VERSION 5.7 ;

BUSBITCHARS "[]" ;
DIVIDERCHAR "/" ;

UNITS
  DATABASE MICRONS 1000 ;
END UNITS

MANUFACTURINGGRID 1.0 ;

PROPERTYDEFINITIONS
  LAYER LEF58_TYPE STRING ;
END PROPERTYDEFINITIONS

SITE CoreSite
  CLASS CORE ;
  SYMMETRY Y ;
  SIZE 30 BY 30 ;
END CoreSite

SITE IO_TOP
  CLASS PAD ;
  SIZE 40 BY 40 ;
END IO_TOP

SITE IO_SIDE
  CLASS PAD ;
  SIZE 40 BY 40 ;
END IO_SIDE

SITE IO_CORNER
  CLASS PAD ;
  SIZE 320 BY 320 ;
END IO_CORNER

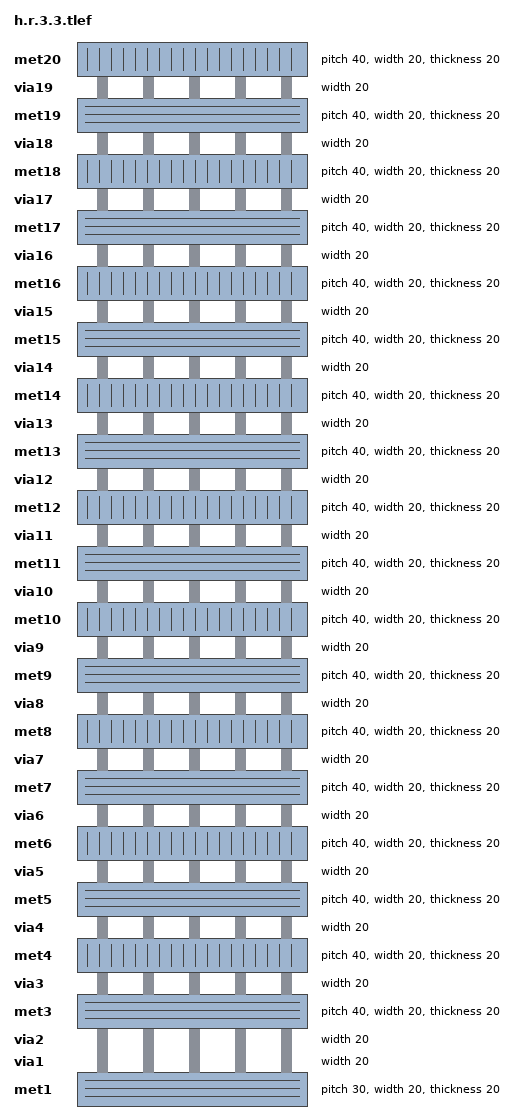
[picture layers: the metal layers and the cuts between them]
LAYER met1
  TYPE ROUTING ;
  DIRECTION HORIZONTAL ;
  MAXWIDTH 20.0 ;
  MINWIDTH 20.0 ;
  WIDTH 20.0 ;
# The pitch for a given routing layer defines the distance between routing tracks in the preferred direction for that layer.
  PITCH 30.0 ;
# Specifies the distance from the top of the ground plane to the bottom of the interconnect.
# HEIGHT  ;
# Specifies the thickness of the interconnect.
  THICKNESS 20.0 ;

END met1

LAYER via1
  TYPE CUT ;
  WIDTH 20.0 ;
END via1

Layer met2
  TYPE ROUTING ;
  DIRECTION VERTICAL ;
  MAXWIDTH 20.0 ;
  MINWIDTH 20.0 ;
  PITCH 40.0 ;
  THICKNESS 20.0 ;
  WIDTH 20.0 ;
END met2

LAYER via2
  TYPE CUT ;
  WIDTH 20.0 ;
END via2

LAYER met3
  TYPE ROUTING ;
  DIRECTION HORIZONTAL ;
  MAXWIDTH 20.0 ;
  MINWIDTH 20.0 ;
  PITCH 40.0 ;
  THICKNESS 20.0 ;
  WIDTH 20.0 ;
END met3

LAYER via3
  TYPE CUT ;
  WIDTH 20.0 ;
END via3

LAYER met4
  TYPE ROUTING ;
  DIRECTION VERTICAL ;
  MAXWIDTH 20.0 ;
  MINWIDTH 20.0 ;
  PITCH 40.0 ;
  THICKNESS 20.0 ;
  WIDTH 20.0 ;
END met4

LAYER via4
  TYPE CUT ;
  WIDTH 20.0 ;
END via4

LAYER met5
  TYPE ROUTING ;
  DIRECTION HORIZONTAL ;
  MAXWIDTH 20.0 ;
  MINWIDTH 20.0 ;
  PITCH 40.0 ;
  THICKNESS 20.0 ;
  WIDTH 20.0 ;
END met5

LAYER via5
  TYPE CUT ;
  WIDTH 20.0 ;
END via5

LAYER met6
  TYPE ROUTING ;
  DIRECTION VERTICAL ;
  MAXWIDTH 20.0 ;
  MINWIDTH 20.0 ;
  PITCH 40.0 ;
  THICKNESS 20.0 ;
  WIDTH 20.0 ;
END met6

LAYER via6
  TYPE CUT ;
  WIDTH 20.0 ;
END via6

LAYER met7
  TYPE ROUTING ;
  DIRECTION HORIZONTAL ;
  MAXWIDTH 20.0 ;
  MINWIDTH 20.0 ;
  PITCH 40.0 ;
  THICKNESS 20.0 ;
  WIDTH 20.0 ;
END met7

LAYER via7
  TYPE CUT ;
  WIDTH 20.0 ;
END via7

LAYER met8
  TYPE ROUTING ;
  DIRECTION VERTICAL ;
  MAXWIDTH 20.0 ;
  MINWIDTH 20.0 ;
  PITCH 40.0 ;
  THICKNESS 20.0 ;
  WIDTH 20.0 ;
END met8

LAYER via8
  TYPE CUT ;
  WIDTH 20.0 ;
END via8

LAYER met9
  TYPE ROUTING ;
  DIRECTION HORIZONTAL ;
  MAXWIDTH 20.0 ;
  MINWIDTH 20.0 ;
  PITCH 40.0 ;
  THICKNESS 20.0 ;
  WIDTH 20.0 ;
END met9

LAYER via9
  TYPE CUT ;
  WIDTH 20.0 ;
END via9

LAYER met10
  TYPE ROUTING ;
  DIRECTION VERTICAL ;
  MAXWIDTH 20.0 ;
  MINWIDTH 20.0 ;
  PITCH 40.0 ;
  THICKNESS 20.0 ;
  WIDTH 20.0 ;
END met10

LAYER via10
  TYPE CUT ;
  WIDTH 20.0 ;
END via10

LAYER met11
  TYPE ROUTING ;
  DIRECTION HORIZONTAL ;
  MAXWIDTH 20.0 ;
  MINWIDTH 20.0 ;
  PITCH 40.0 ;
  THICKNESS 20.0 ;
  WIDTH 20.0 ;
END met11

LAYER via11
  TYPE CUT ;
  WIDTH 20.0 ;
END via11

LAYER met12
  TYPE ROUTING ;
  DIRECTION VERTICAL ;
  MAXWIDTH 20.0 ;
  MINWIDTH 20.0 ;
  PITCH 40.0 ;
  THICKNESS 20.0 ;
  WIDTH 20.0 ;
END met12

LAYER via12
  TYPE CUT ;
  WIDTH 20.0 ;
END via12

LAYER met13
  TYPE ROUTING ;
  DIRECTION HORIZONTAL ;
  MAXWIDTH 20.0 ;
  MINWIDTH 20.0 ;
  PITCH 40.0 ;
  THICKNESS 20.0 ;
  WIDTH 20.0 ;
END met13

LAYER via13
  TYPE CUT ;
  WIDTH 20.0 ;
END via13

LAYER met14
  TYPE ROUTING ;
  DIRECTION VERTICAL ;
  MAXWIDTH 20.0 ;
  MINWIDTH 20.0 ;
  PITCH 40.0 ;
  THICKNESS 20.0 ;
  WIDTH 20.0 ;
END met14

LAYER via14
  TYPE CUT ;
  WIDTH 20.0 ;
END via14

LAYER met15
  TYPE ROUTING ;
  DIRECTION HORIZONTAL ;
  MAXWIDTH 20.0 ;
  MINWIDTH 20.0 ;
  PITCH 40.0 ;
  THICKNESS 20.0 ;
  WIDTH 20.0 ;
END met15

LAYER via15
  TYPE CUT ;
  WIDTH 20.0 ;
END via15

LAYER met16
  TYPE ROUTING ;
  DIRECTION VERTICAL ;
  MAXWIDTH 20.0 ;
  MINWIDTH 20.0 ;
  PITCH 40.0 ;
  THICKNESS 20.0 ;
  WIDTH 20.0 ;
END met16

LAYER via16
  TYPE CUT ;
  WIDTH 20.0 ;
END via16

LAYER met17
  TYPE ROUTING ;
  DIRECTION HORIZONTAL ;
  MAXWIDTH 20.0 ;
  MINWIDTH 20.0 ;
  PITCH 40.0 ;
  THICKNESS 20.0 ;
  WIDTH 20.0 ;
END met17

LAYER via17
  TYPE CUT ;
  WIDTH 20.0 ;
END via17

LAYER met18
  TYPE ROUTING ;
  DIRECTION VERTICAL ;
  MAXWIDTH 20.0 ;
  MINWIDTH 20.0 ;
  PITCH 40.0 ;
  THICKNESS 20.0 ;
  WIDTH 20.0 ;
END met18

LAYER via18
  TYPE CUT ;
  WIDTH 20.0 ;
END via18

LAYER met19
  TYPE ROUTING ;
  DIRECTION HORIZONTAL ;
  MAXWIDTH 20.0 ;
  MINWIDTH 20.0 ;
  PITCH 40.0 ;
  THICKNESS 20.0 ;
  WIDTH 20.0 ;
END met19

LAYER via19
  TYPE CUT ;
  WIDTH 20.0 ;
END via19

LAYER met20
  TYPE ROUTING ;
  DIRECTION VERTICAL ;
  MAXWIDTH 20.0 ;
  MINWIDTH 20.0 ;
  PITCH 40.0 ;
  THICKNESS 20.0 ;
  WIDTH 20.0 ;
END met20

VIA M1M2_PR DEFAULT
  LAYER via1 ;
    RECT -10.0 -10.0 10.0 10.0 ;
  LAYER met1 ;
    RECT -10.0 -10.0 10.0 10.0 ;
  LAYER met2 ;
    RECT -10.0 -10.0 10.0 10.0 ;
END M1M2_PR

VIA M2M3_PR DEFAULT
  LAYER via2 ;
    RECT -10.0 -10.0 10.0 10.0 ;
  LAYER met2 ;
    RECT -10.0 -10.0 10.0 10.0 ;
  LAYER met3 ;
    RECT -10.0 -10.0 10.0 10.0 ;
END M2M3_PR

VIA M3M4_PR DEFAULT
  LAYER via3 ;
    RECT -10.0 -10.0 10.0 10.0 ;
  LAYER met3 ;
    RECT -10.0 -10.0 10.0 10.0 ;
  LAYER met4 ;
    RECT -10.0 -10.0 10.0 10.0 ;
END M3M4_PR

VIA M4M5_PR DEFAULT
  LAYER via4 ;
    RECT -10.0 -10.0 10.0 10.0 ;
  LAYER met4 ;
    RECT -10.0 -10.0 10.0 10.0 ;
  LAYER met5 ;
    RECT -10.0 -10.0 10.0 10.0 ;
END M4M5_PR

VIA M5M6_PR DEFAULT
  LAYER via5 ;
    RECT -10.0 -10.0 10.0 10.0 ;
  LAYER met5 ;
    RECT -10.0 -10.0 10.0 10.0 ;
  LAYER met6 ;
    RECT -10.0 -10.0 10.0 10.0 ;
END M5M6_PR

VIA M6M7_PR DEFAULT
  LAYER via6 ;
    RECT -10.0 -10.0 10.0 10.0 ;
  LAYER met6 ;
    RECT -10.0 -10.0 10.0 10.0 ;
  LAYER met7 ;
    RECT -10.0 -10.0 10.0 10.0 ;
END M6M7_PR

VIA M7M8_PR DEFAULT
  LAYER via7 ;
    RECT -10.0 -10.0 10.0 10.0 ;
  LAYER met7 ;
    RECT -10.0 -10.0 10.0 10.0 ;
  LAYER met8 ;
    RECT -10.0 -10.0 10.0 10.0 ;
END M7M8_PR

VIA M8M9_PR DEFAULT
  LAYER via8 ;
    RECT -10.0 -10.0 10.0 10.0 ;
  LAYER met8 ;
    RECT -10.0 -10.0 10.0 10.0 ;
  LAYER met9 ;
    RECT -10.0 -10.0 10.0 10.0 ;
END M8M9_PR

VIA M9M10_PR DEFAULT
  LAYER via9 ;
    RECT -10.0 -10.0 10.0 10.0 ;
  LAYER met9 ;
    RECT -10.0 -10.0 10.0 10.0 ;
  LAYER met10 ;
    RECT -10.0 -10.0 10.0 10.0 ;
END M9M10_PR
VIA M10M11_PR DEFAULT
  LAYER via10 ;
    RECT -10.0 -10.0 10.0 10.0 ;
  LAYER met10 ;
    RECT -10.0 -10.0 10.0 10.0 ;
  LAYER met11 ;
    RECT -10.0 -10.0 10.0 10.0 ;
END M10M11_PR



VIA M11M12_PR DEFAULT
  LAYER via11 ;
    RECT -10.0 -10.0 10.0 10.0 ;
  LAYER met11 ;
    RECT -10.0 -10.0 10.0 10.0 ;
  LAYER met12 ;
    RECT -10.0 -10.0 10.0 10.0 ;
END M11M12_PR



VIA M12M13_PR DEFAULT
  LAYER via12 ;
    RECT -10.0 -10.0 10.0 10.0 ;
  LAYER met12 ;
    RECT -10.0 -10.0 10.0 10.0 ;
  LAYER met13 ;
    RECT -10.0 -10.0 10.0 10.0 ;
END M12M13_PR



VIA M13M14_PR DEFAULT
  LAYER via13 ;
    RECT -10.0 -10.0 10.0 10.0 ;
  LAYER met13 ;
    RECT -10.0 -10.0 10.0 10.0 ;
  LAYER met14 ;
    RECT -10.0 -10.0 10.0 10.0 ;
END M13M14_PR



VIA M14M15_PR DEFAULT
  LAYER via14 ;
    RECT -10.0 -10.0 10.0 10.0 ;
  LAYER met14 ;
    RECT -10.0 -10.0 10.0 10.0 ;
  LAYER met15 ;
    RECT -10.0 -10.0 10.0 10.0 ;
END M14M15_PR



VIA M15M16_PR DEFAULT
  LAYER via15 ;
    RECT -10.0 -10.0 10.0 10.0 ;
  LAYER met15 ;
    RECT -10.0 -10.0 10.0 10.0 ;
  LAYER met16 ;
    RECT -10.0 -10.0 10.0 10.0 ;
END M15M16_PR



VIA M16M17_PR DEFAULT
  LAYER via16 ;
    RECT -10.0 -10.0 10.0 10.0 ;
  LAYER met16 ;
    RECT -10.0 -10.0 10.0 10.0 ;
  LAYER met17 ;
    RECT -10.0 -10.0 10.0 10.0 ;
END M16M17_PR



VIA M17M18_PR DEFAULT
  LAYER via17 ;
    RECT -10.0 -10.0 10.0 10.0 ;
  LAYER met17 ;
    RECT -10.0 -10.0 10.0 10.0 ;
  LAYER met18 ;
    RECT -10.0 -10.0 10.0 10.0 ;
END M17M18_PR



VIA M18M19_PR DEFAULT
  LAYER via18 ;
    RECT -10.0 -10.0 10.0 10.0 ;
  LAYER met18 ;
    RECT -10.0 -10.0 10.0 10.0 ;
  LAYER met19 ;
    RECT -10.0 -10.0 10.0 10.0 ;
END M18M19_PR



VIA M19M20_PR DEFAULT
  LAYER via19 ;
    RECT -10.0 -10.0 10.0 10.0 ;
  LAYER met19 ;
    RECT -10.0 -10.0 10.0 10.0 ;
  LAYER met20 ;
    RECT -10.0 -10.0 10.0 10.0 ;
END M19M20_PR


END LIBRARY
